VERSION 5.7 ;
  NOWIREEXTENSIONATPIN ON ;
  DIVIDERCHAR "/" ;
  BUSBITCHARS "[]" ;
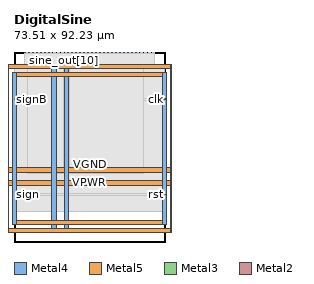
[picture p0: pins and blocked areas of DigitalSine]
MACRO DigitalSine
  CLASS BLOCK ;
  FOREIGN DigitalSine ;
  ORIGIN 0.000 0.000 ;
  SIZE 73.510 BY 92.230 ;
  PIN VGND
    DIRECTION INOUT ;
    USE GROUND ;
    PORT
      LAYER Metal4 ;
        RECT -4.740 4.620 -2.740 86.100 ;
    END
    PORT
      LAYER Metal5 ;
        RECT -4.740 4.620 78.180 6.620 ;
    END
    PORT
      LAYER Metal5 ;
        RECT -4.740 84.100 78.180 86.100 ;
    END
    PORT
      LAYER Metal4 ;
        RECT 76.180 4.620 78.180 86.100 ;
    END
    PORT
      LAYER Metal4 ;
        RECT 24.460 4.620 26.660 86.100 ;
    END
    PORT
      LAYER Metal5 ;
        RECT -4.740 33.820 78.180 36.020 ;
    END
  END VGND
  PIN VPWR
    DIRECTION INOUT ;
    USE POWER ;
    PORT
      LAYER Metal4 ;
        RECT -0.740 8.620 1.260 82.100 ;
    END
    PORT
      LAYER Metal5 ;
        RECT -0.740 8.620 74.180 10.620 ;
    END
    PORT
      LAYER Metal5 ;
        RECT -0.740 80.100 74.180 82.100 ;
    END
    PORT
      LAYER Metal4 ;
        RECT 72.180 8.620 74.180 82.100 ;
    END
    PORT
      LAYER Metal4 ;
        RECT 18.260 4.620 20.460 86.100 ;
    END
    PORT
      LAYER Metal5 ;
        RECT -4.740 27.620 78.180 29.820 ;
    END
  END VPWR
  PIN clk
    DIRECTION INPUT ;
    USE SIGNAL ;
    ANTENNAGATEAREA 0.725400 ;
    PORT
      LAYER Metal3 ;
        RECT 73.110 69.100 73.510 69.500 ;
    END
  END clk
  PIN rst
    DIRECTION INPUT ;
    USE SIGNAL ;
    ANTENNAGATEAREA 0.180700 ;
    PORT
      LAYER Metal3 ;
        RECT 73.110 22.900 73.510 23.300 ;
    END
  END rst
  PIN sign
    DIRECTION OUTPUT ;
    USE SIGNAL ;
    ANTENNADIFFAREA 0.708600 ;
    PORT
      LAYER Metal3 ;
        RECT 0.000 22.900 0.400 23.300 ;
    END
  END sign
  PIN signB
    DIRECTION OUTPUT ;
    USE SIGNAL ;
    ANTENNADIFFAREA 0.708600 ;
    PORT
      LAYER Metal3 ;
        RECT 0.000 69.100 0.400 69.500 ;
    END
  END signB
  PIN sine_out[0]
    DIRECTION OUTPUT ;
    USE SIGNAL ;
    ANTENNADIFFAREA 0.708600 ;
    PORT
      LAYER Metal2 ;
        RECT 5.080 91.830 5.480 92.230 ;
    END
  END sine_out[0]
  PIN sine_out[10]
    DIRECTION OUTPUT ;
    USE SIGNAL ;
    ANTENNADIFFAREA 0.708600 ;
    PORT
      LAYER Metal2 ;
        RECT 24.280 91.830 24.680 92.230 ;
    END
  END sine_out[10]
  PIN sine_out[11]
    DIRECTION OUTPUT ;
    USE SIGNAL ;
    ANTENNADIFFAREA 0.708600 ;
    PORT
      LAYER Metal2 ;
        RECT 26.200 91.830 26.600 92.230 ;
    END
  END sine_out[11]
  PIN sine_out[12]
    DIRECTION OUTPUT ;
    USE SIGNAL ;
    ANTENNADIFFAREA 0.708600 ;
    PORT
      LAYER Metal2 ;
        RECT 28.120 91.830 28.520 92.230 ;
    END
  END sine_out[12]
  PIN sine_out[13]
    DIRECTION OUTPUT ;
    USE SIGNAL ;
    ANTENNADIFFAREA 0.708600 ;
    PORT
      LAYER Metal2 ;
        RECT 30.040 91.830 30.440 92.230 ;
    END
  END sine_out[13]
  PIN sine_out[14]
    DIRECTION OUTPUT ;
    USE SIGNAL ;
    ANTENNADIFFAREA 0.708600 ;
    PORT
      LAYER Metal2 ;
        RECT 31.960 91.830 32.360 92.230 ;
    END
  END sine_out[14]
  PIN sine_out[15]
    DIRECTION OUTPUT ;
    USE SIGNAL ;
    ANTENNADIFFAREA 0.708600 ;
    PORT
      LAYER Metal2 ;
        RECT 33.880 91.830 34.280 92.230 ;
    END
  END sine_out[15]
  PIN sine_out[16]
    DIRECTION OUTPUT ;
    USE SIGNAL ;
    ANTENNADIFFAREA 0.708600 ;
    PORT
      LAYER Metal2 ;
        RECT 35.800 91.830 36.200 92.230 ;
    END
  END sine_out[16]
  PIN sine_out[17]
    DIRECTION OUTPUT ;
    USE SIGNAL ;
    ANTENNADIFFAREA 0.708600 ;
    PORT
      LAYER Metal2 ;
        RECT 37.720 91.830 38.120 92.230 ;
    END
  END sine_out[17]
  PIN sine_out[18]
    DIRECTION OUTPUT ;
    USE SIGNAL ;
    ANTENNADIFFAREA 0.708600 ;
    PORT
      LAYER Metal2 ;
        RECT 39.640 91.830 40.040 92.230 ;
    END
  END sine_out[18]
  PIN sine_out[19]
    DIRECTION OUTPUT ;
    USE SIGNAL ;
    ANTENNADIFFAREA 0.708600 ;
    PORT
      LAYER Metal2 ;
        RECT 41.560 91.830 41.960 92.230 ;
    END
  END sine_out[19]
  PIN sine_out[1]
    DIRECTION OUTPUT ;
    USE SIGNAL ;
    ANTENNADIFFAREA 0.708600 ;
    PORT
      LAYER Metal2 ;
        RECT 7.000 91.830 7.400 92.230 ;
    END
  END sine_out[1]
  PIN sine_out[20]
    DIRECTION OUTPUT ;
    USE SIGNAL ;
    ANTENNADIFFAREA 0.708600 ;
    PORT
      LAYER Metal2 ;
        RECT 43.480 91.830 43.880 92.230 ;
    END
  END sine_out[20]
  PIN sine_out[21]
    DIRECTION OUTPUT ;
    USE SIGNAL ;
    ANTENNADIFFAREA 0.708600 ;
    PORT
      LAYER Metal2 ;
        RECT 45.400 91.830 45.800 92.230 ;
    END
  END sine_out[21]
  PIN sine_out[22]
    DIRECTION OUTPUT ;
    USE SIGNAL ;
    ANTENNADIFFAREA 0.708600 ;
    PORT
      LAYER Metal2 ;
        RECT 47.320 91.830 47.720 92.230 ;
    END
  END sine_out[22]
  PIN sine_out[23]
    DIRECTION OUTPUT ;
    USE SIGNAL ;
    ANTENNADIFFAREA 0.708600 ;
    PORT
      LAYER Metal2 ;
        RECT 49.240 91.830 49.640 92.230 ;
    END
  END sine_out[23]
  PIN sine_out[24]
    DIRECTION OUTPUT ;
    USE SIGNAL ;
    ANTENNADIFFAREA 0.708600 ;
    PORT
      LAYER Metal2 ;
        RECT 51.160 91.830 51.560 92.230 ;
    END
  END sine_out[24]
  PIN sine_out[25]
    DIRECTION OUTPUT ;
    USE SIGNAL ;
    ANTENNADIFFAREA 0.708600 ;
    PORT
      LAYER Metal2 ;
        RECT 53.080 91.830 53.480 92.230 ;
    END
  END sine_out[25]
  PIN sine_out[26]
    DIRECTION OUTPUT ;
    USE SIGNAL ;
    ANTENNADIFFAREA 0.708600 ;
    PORT
      LAYER Metal2 ;
        RECT 55.000 91.830 55.400 92.230 ;
    END
  END sine_out[26]
  PIN sine_out[27]
    DIRECTION OUTPUT ;
    USE SIGNAL ;
    ANTENNADIFFAREA 0.708600 ;
    PORT
      LAYER Metal2 ;
        RECT 56.920 91.830 57.320 92.230 ;
    END
  END sine_out[27]
  PIN sine_out[28]
    DIRECTION OUTPUT ;
    USE SIGNAL ;
    ANTENNADIFFAREA 0.708600 ;
    PORT
      LAYER Metal2 ;
        RECT 58.840 91.830 59.240 92.230 ;
    END
  END sine_out[28]
  PIN sine_out[29]
    DIRECTION OUTPUT ;
    USE SIGNAL ;
    ANTENNADIFFAREA 0.708600 ;
    PORT
      LAYER Metal2 ;
        RECT 60.760 91.830 61.160 92.230 ;
    END
  END sine_out[29]
  PIN sine_out[2]
    DIRECTION OUTPUT ;
    USE SIGNAL ;
    ANTENNADIFFAREA 0.708600 ;
    PORT
      LAYER Metal2 ;
        RECT 8.920 91.830 9.320 92.230 ;
    END
  END sine_out[2]
  PIN sine_out[30]
    DIRECTION OUTPUT ;
    USE SIGNAL ;
    ANTENNADIFFAREA 0.708600 ;
    PORT
      LAYER Metal2 ;
        RECT 62.680 91.830 63.080 92.230 ;
    END
  END sine_out[30]
  PIN sine_out[31]
    DIRECTION OUTPUT ;
    USE SIGNAL ;
    ANTENNADIFFAREA 0.708600 ;
    PORT
      LAYER Metal2 ;
        RECT 64.600 91.830 65.000 92.230 ;
    END
  END sine_out[31]
  PIN sine_out[32]
    DIRECTION OUTPUT ;
    USE SIGNAL ;
    ANTENNADIFFAREA 0.708600 ;
    PORT
      LAYER Metal2 ;
        RECT 66.520 91.830 66.920 92.230 ;
    END
  END sine_out[32]
  PIN sine_out[3]
    DIRECTION OUTPUT ;
    USE SIGNAL ;
    ANTENNADIFFAREA 0.708600 ;
    PORT
      LAYER Metal2 ;
        RECT 10.840 91.830 11.240 92.230 ;
    END
  END sine_out[3]
  PIN sine_out[4]
    DIRECTION OUTPUT ;
    USE SIGNAL ;
    ANTENNADIFFAREA 0.708600 ;
    PORT
      LAYER Metal2 ;
        RECT 12.760 91.830 13.160 92.230 ;
    END
  END sine_out[4]
  PIN sine_out[5]
    DIRECTION OUTPUT ;
    USE SIGNAL ;
    ANTENNADIFFAREA 0.708600 ;
    PORT
      LAYER Metal2 ;
        RECT 14.680 91.830 15.080 92.230 ;
    END
  END sine_out[5]
  PIN sine_out[6]
    DIRECTION OUTPUT ;
    USE SIGNAL ;
    ANTENNADIFFAREA 0.708600 ;
    PORT
      LAYER Metal2 ;
        RECT 16.600 91.830 17.000 92.230 ;
    END
  END sine_out[6]
  PIN sine_out[7]
    DIRECTION OUTPUT ;
    USE SIGNAL ;
    ANTENNADIFFAREA 0.708600 ;
    PORT
      LAYER Metal2 ;
        RECT 18.520 91.830 18.920 92.230 ;
    END
  END sine_out[7]
  PIN sine_out[8]
    DIRECTION OUTPUT ;
    USE SIGNAL ;
    ANTENNADIFFAREA 0.708600 ;
    PORT
      LAYER Metal2 ;
        RECT 20.440 91.830 20.840 92.230 ;
    END
  END sine_out[8]
  PIN sine_out[9]
    DIRECTION OUTPUT ;
    USE SIGNAL ;
    ANTENNADIFFAREA 0.708600 ;
    PORT
      LAYER Metal2 ;
        RECT 22.360 91.830 22.760 92.230 ;
    END
  END sine_out[9]
  OBS
      LAYER GatPoly ;
        RECT 5.760 14.970 67.680 75.750 ;
      LAYER Metal1 ;
        RECT 5.760 14.900 67.680 75.820 ;
      LAYER Metal2 ;
        RECT 5.690 91.620 6.790 91.830 ;
        RECT 7.610 91.620 8.710 91.830 ;
        RECT 9.530 91.620 10.630 91.830 ;
        RECT 11.450 91.620 12.550 91.830 ;
        RECT 13.370 91.620 14.470 91.830 ;
        RECT 15.290 91.620 16.390 91.830 ;
        RECT 17.210 91.620 18.310 91.830 ;
        RECT 19.130 91.620 20.230 91.830 ;
        RECT 21.050 91.620 22.150 91.830 ;
        RECT 22.970 91.620 24.070 91.830 ;
        RECT 24.890 91.620 25.990 91.830 ;
        RECT 26.810 91.620 27.910 91.830 ;
        RECT 28.730 91.620 29.830 91.830 ;
        RECT 30.650 91.620 31.750 91.830 ;
        RECT 32.570 91.620 33.670 91.830 ;
        RECT 34.490 91.620 35.590 91.830 ;
        RECT 36.410 91.620 37.510 91.830 ;
        RECT 38.330 91.620 39.430 91.830 ;
        RECT 40.250 91.620 41.350 91.830 ;
        RECT 42.170 91.620 43.270 91.830 ;
        RECT 44.090 91.620 45.190 91.830 ;
        RECT 46.010 91.620 47.110 91.830 ;
        RECT 47.930 91.620 49.030 91.830 ;
        RECT 49.850 91.620 50.950 91.830 ;
        RECT 51.770 91.620 52.870 91.830 ;
        RECT 53.690 91.620 54.790 91.830 ;
        RECT 55.610 91.620 56.710 91.830 ;
        RECT 57.530 91.620 58.630 91.830 ;
        RECT 59.450 91.620 60.550 91.830 ;
        RECT 61.370 91.620 62.470 91.830 ;
        RECT 63.290 91.620 64.390 91.830 ;
        RECT 65.210 91.620 66.310 91.830 ;
        RECT 67.130 91.620 68.265 91.830 ;
        RECT 5.180 14.975 68.265 91.620 ;
      LAYER Metal3 ;
        RECT 0.400 69.710 73.110 84.105 ;
        RECT 0.610 68.890 72.900 69.710 ;
        RECT 0.400 23.510 73.110 68.890 ;
        RECT 0.610 22.690 72.900 23.510 ;
        RECT 0.400 15.020 73.110 22.690 ;
      LAYER Metal4 ;
        RECT 6.620 33.035 18.050 84.145 ;
        RECT 20.670 33.035 24.250 84.145 ;
        RECT 26.870 33.035 62.980 84.145 ;
  END
END DigitalSine
END LIBRARY

